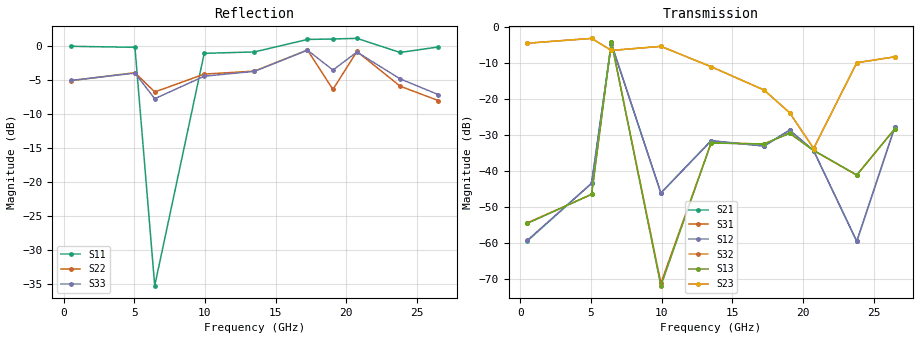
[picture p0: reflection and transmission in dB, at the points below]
! Mini-Circuits
! BBFCG2-672+
! Reference Information: Unit 10, Test Board, eCal w/ Auto Port Extension & Match Correction
! Temperature: +25 Degrees Celsius
# Hz S  dB  R 50
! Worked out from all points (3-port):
!   891 points, 500 MHz to 26.5 GHz, reference 50 ohm
!   strongest paths, dB at 500 MHz, 2.72 GHz, 6.6 GHz, 15.4 GHz, 26.5 GHz:
!     S32: -4.5, -9.0, -6.5, -24.9, -8.2
!     S31: -54.4, -35.2, -4.0, -32.3, -28.2
!     S21: -59.4, -48.3, -4.4, -31.5, -27.6
!   lowest |S11| = -35.3 dB at 6.45 GHz (marker M1), VSWR 1.04, Z = 50.5 + j1.66 ohm
!   |S11| at or under -10 dB: 6.103 GHz to 7.71 GHz (1.608 GHz wide, 23.3 % of centre); 17.96 GHz to 18.22 GHz (259.1 MHz wide, 1.43 % of centre)
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5e8  0.02 179.5  -59.23 -139.4  -54.52 110.5
     -59.41 -137.8  -5.06 -150.2  -4.48 -30.1
     -54.38 110.6  -4.47 -30.1  -5.02 -150.5
5.05e9  -0.13 124.2  -43.37 35.1  -46.43 118.6
        -43.38 35.1  -3.87 143.5  -3.13 -137.0
        -46.45 119.0  -3.14 -137.0  -3.93 129.6
6.45e9  -35.28 72.5  -4.62 -119.6  -4.04 64.7
        -4.62 -119.6  -6.72 166.3  -6.48 164.4
        -4.04 64.8  -6.48 164.4  -7.71 177.4
9.95e9  -1.02 1.9  -46.07 -75.3  -71.81 37.4
        -46.09 -74.9  -4.08 64.6  -5.35 136.1
        -71.13 33.5  -5.35 136.1  -4.39 27.8
1.35e10  -0.81 8.2  -31.55 -134.1  -32.19 -138.0
         -31.55 -134.3  -3.64 58.3  -10.99 170.8
         -32.16 -137.9  -10.99 170.9  -3.67 41.0
1.725e10  1.03 1.0  -33.03 -135.7  -32.46 -135.1
          -33.02 -135.8  -0.53 45.7  -17.49 176.9
          -32.45 -134.9  -17.49 177.0  -0.55 40.2
1.905e10  1.10 -170.7  -28.63 161.5  -29.46 151.5
          -28.61 161.4  -6.34 -115.0  -23.77 93.2
          -29.44 151.6  -23.77 93.3  -3.48 -127.4
2.075e10  1.19 -94.8  -34.33 110.0  -34.22 99.1
          -34.31 110.0  -0.74 -55.5  -33.73 -155.7
          -34.29 98.9  -33.68 -155.6  -0.83 -62.6
2.38e10  -0.89 -104.2  -59.50 -137.5  -41.07 -99.6
         -59.49 -136.7  -5.86 98.1  -9.89 -8.1
         -41.12 -100.0  -9.89 -7.8  -4.78 55.5
2.65e10  -0.08 135.5  -27.66 -6.0  -28.22 -4.2
         -27.64 -6.1  -7.98 112.5  -8.25 -36.7
         -28.18 -4.1  -8.25 -36.5  -7.10 106.7
